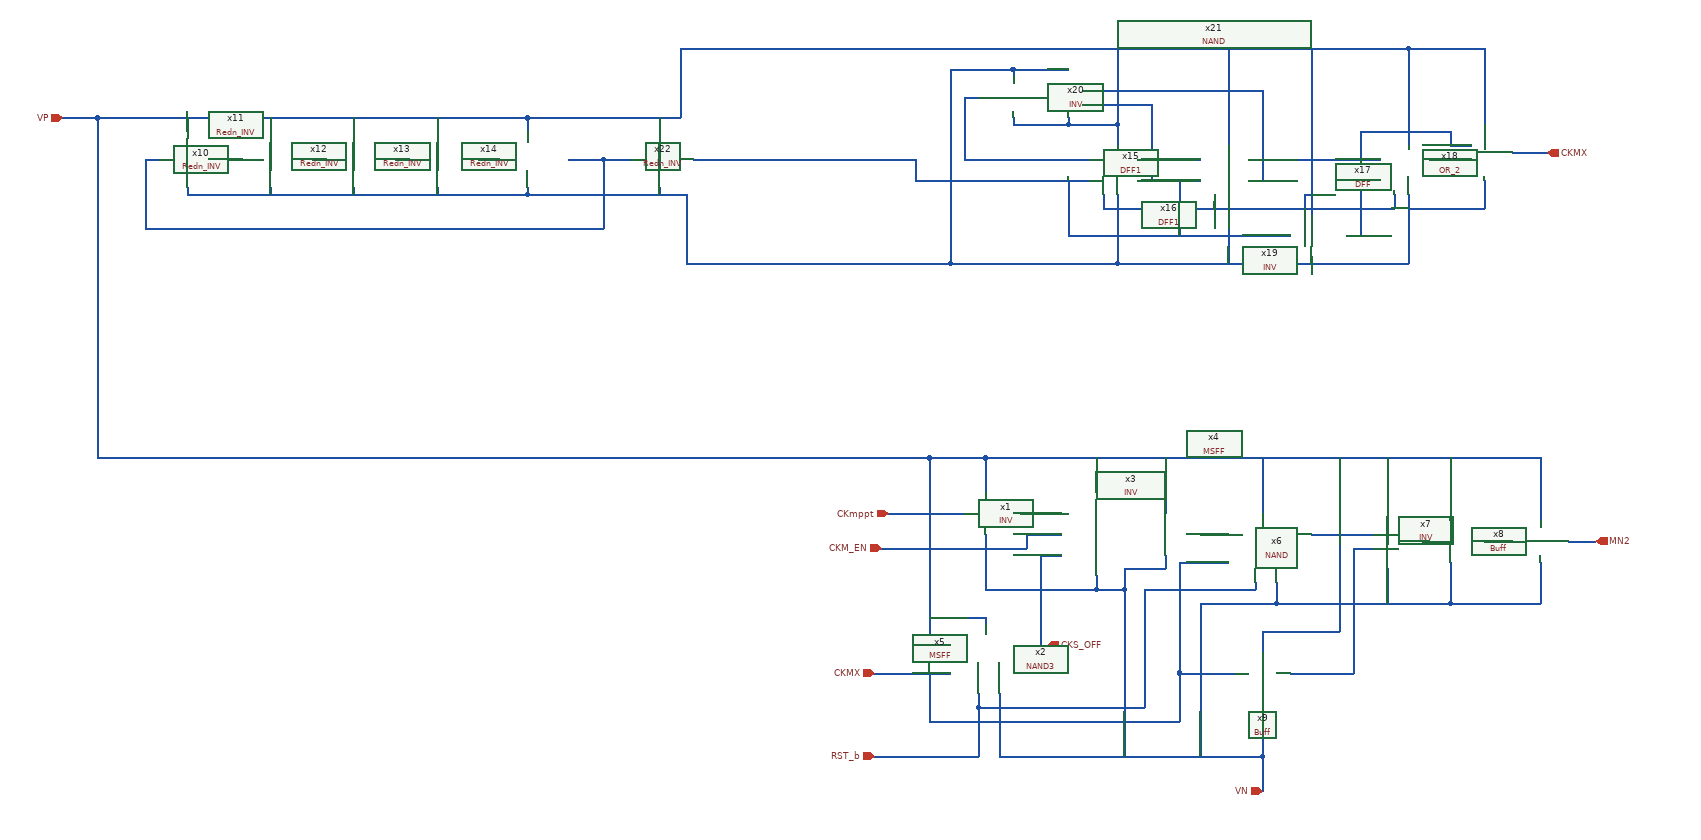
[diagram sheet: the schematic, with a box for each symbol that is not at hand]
v {xschem version=3.0.0 file_version=1.2 }
G {}
K {}
V {}
S {}
E {}
N 450 -550 510 -550 {
lab=#net1}
N 320 -550 370 -550 {
lab=CKmppt}
N 490 -520 510 -520 {
lab=CKmppt}
N 460 -520 490 -520 {
lab=CKmppt}
N 460 -520 460 -500 {
lab=CKmppt}
N 320 -500 460 -500 {
lab=CKmppt}
N 490 -490 510 -490 {
lab=CKS_OFF}
N 870 -520 960 -520 {
lab=#net2}
N 1120 -510 1160 -510 {
lab=#net3}
N 1240 -510 1280 -510 {
lab=MN2}
N 840 -320 930 -320 {
lab=#net4}
N 930 -500 930 -320 {
lab=#net4}
N 930 -500 960 -500 {
lab=#net4}
N 320 -360 350 -360 {
lab=CKmppt}
N 320 -420 320 -360 {
lab=CKmppt}
N 320 -400 380 -400 {
lab=CKmppt}
N 790 -450 790 -440 {
lab=RST_b}
N 290 -320 350 -320 {
lab=CKMX}
N 320 -320 320 -270 {
lab=CKMX}
N 320 -270 320 -250 {
lab=CKMX}
N 320 -250 680 -250 {
lab=CKMX}
N 680 -310 680 -250 {
lab=CKMX}
N 680 -320 680 -310 {
lab=CKMX}
N 680 -320 760 -320 {
lab=CKMX}
N 630 -400 630 -280 {
lab=RST_b}
N 390 -270 630 -270 {
lab=RST_b}
N 390 -290 390 -280 {
lab=RST_b}
N 630 -280 630 -270 {
lab=RST_b}
N 390 -280 390 -270 {
lab=RST_b}
N 390 -270 390 -200 {
lab=RST_b}
N 290 -200 390 -200 {
lab=RST_b}
N 240 -200 290 -200 {
lab=RST_b}
N 240 -320 290 -320 {
lab=CKMX}
N 250 -500 320 -500 {
lab=CKM_EN}
N 260 -550 320 -550 {
lab=CKmppt}
N 470 -360 490 -360 {
lab=CKS_OFF}
N 710 -520 750 -520 {
lab=#net5}
N 680 -450 680 -320 {
lab=CKMX}
N 700 -480 750 -480 {
lab=CKMX}
N 420 -290 420 -200 {
lab=#net6}
N 420 -200 800 -200 {
lab=#net6}
N 800 -290 800 -200 {
lab=#net6}
N 820 -450 820 -430 {
lab=#net6}
N 680 -480 680 -450 {
lab=CKMX}
N 680 -480 700 -480 {
lab=CKMX}
N 630 -440 630 -400 {
lab=RST_b}
N 630 -440 790 -440 {
lab=RST_b}
N 820 -430 820 -420 {
lab=#net6}
N 710 -420 820 -420 {
lab=#net6}
N 710 -420 710 -200 {
lab=#net6}
N 800 -200 800 -150 {
lab=#net6}
N 400 -520 400 -450 {
lab=#net6}
N 400 -450 400 -440 {
lab=#net6}
N 400 -440 560 -440 {
lab=#net6}
N 560 -460 560 -440 {
lab=#net6}
N 600 -440 600 -200 {
lab=#net6}
N 660 -490 660 -470 {
lab=#net6}
N 600 -470 660 -470 {
lab=#net6}
N 600 -470 600 -440 {
lab=#net6}
N 560 -440 600 -440 {
lab=#net6}
N 820 -420 990 -420 {
lab=#net6}
N 1200 -480 1200 -460 {
lab=#net6}
N 1070 -480 1070 -420 {
lab=#net6}
N 1200 -460 1200 -420 {
lab=#net6}
N 1070 -420 1200 -420 {
lab=#net6}
N 990 -420 1070 -420 {
lab=#net6}
N 400 -630 1190 -630 {
lab=CKmppt}
N 1190 -630 1200 -630 {
lab=CKmppt}
N 1200 -630 1200 -540 {
lab=CKmppt}
N 1070 -630 1070 -540 {
lab=CKmppt}
N 800 -630 800 -550 {
lab=CKmppt}
N 660 -630 660 -550 {
lab=CKmppt}
N 560 -630 560 -580 {
lab=CKmppt}
N 400 -630 400 -580 {
lab=CKmppt}
N 800 -380 800 -350 {
lab=CKmppt}
N 800 -380 910 -380 {
lab=CKmppt}
N 910 -630 910 -380 {
lab=CKmppt}
N 480 -490 490 -490 {
lab=CKS_OFF}
N 480 -490 480 -360 {
lab=CKS_OFF}
N 380 -400 400 -400 {
lab=CKmppt}
N 400 -400 400 -390 {
lab=CKmppt}
N 980 -630 980 -540 {
lab=CKmppt}
N 980 -470 980 -420 {
lab=#net6}
N 1030 -510 1040 -510 {
lab=#net7}
N -690 -1060 -670 -1060 {
lab=#net8}
N -570 -1060 -550 -1060 {
lab=#net9}
N -450 -1060 -430 -1060 {
lab=#net10}
N -330 -1060 -300 -1060 {
lab=#net11}
N -750 -1020 -750 -1010 {
lab=#net12}
N -750 -1010 -260 -1010 {
lab=#net12}
N -260 -1020 -260 -1010 {
lab=#net12}
N -390 -1020 -390 -1010 {
lab=#net12}
N -510 -1020 -510 -1010 {
lab=#net12}
N -630 -1020 -630 -1010 {
lab=#net12}
N -810 -1060 -790 -1060 {
lab=#net13}
N -810 -1060 -810 -960 {
lab=#net13}
N -200 -1060 -150 -1060 {
lab=#net13}
N -200 -1060 -150 -1060 {
lab=#net13}
N -810 -1120 -260 -1120 {
lab=CKmppt}
N -260 -1120 -260 -1100 {
lab=CKmppt}
N -390 -1120 -390 -1100 {
lab=CKmppt}
N -510 -1120 -510 -1100 {
lab=CKmppt}
N -630 -1120 -630 -1100 {
lab=CKmppt}
N -750 -1120 -750 -1100 {
lab=CKmppt}
N -150 -1060 -120 -1060 {
lab=#net13}
N -150 -1060 -150 -960 {
lab=#net13}
N -810 -960 -150 -960 {
lab=#net13}
N -260 -1120 -40 -1120 {
lab=CKmppt}
N -260 -1010 -30 -1010 {
lab=#net12}
N -120 -1060 -110 -1060 {
lab=#net13}
N 520 -1030 520 -980 {
lab=#net14}
N 680 -1030 710 -1030 {
lab=#net14}
N 750 -1110 750 -1080 {
lab=CKmppt}
N 590 -1110 590 -1080 {
lab=CKmppt}
N 520 -980 520 -960 {
lab=#net14}
N 520 -950 840 -950 {
lab=#net14}
N 920 -950 940 -950 {
lab=#net15}
N 940 -1030 940 -960 {
lab=#net15}
N 940 -1030 970 -1030 {
lab=#net15}
N 590 -1010 590 -910 {
lab=#net12}
N 590 -910 1010 -910 {
lab=#net12}
N 1010 -1010 1010 -910 {
lab=#net12}
N 750 -1010 750 -910 {
lab=#net12}
N 940 -960 940 -950 {
lab=#net15}
N 520 -960 520 -950 {
lab=#net14}
N 570 -1010 570 -990 {
lab=CKmppt}
N 870 -1110 870 -980 {
lab=CKmppt}
N 570 -990 990 -990 {
lab=CKmppt}
N 990 -1010 990 -990 {
lab=CKmppt}
N 730 -1010 730 -990 {
lab=CKmppt}
N 870 -920 870 -910 {
lab=#net12}
N 1010 -1110 1010 -1080 {
lab=CKmppt}
N 680 -1030 680 -950 {
lab=#net14}
N 350 -1220 520 -1220 {
lab=CKmppt}
N 520 -1220 1010 -1220 {
lab=CKmppt}
N 1010 -1220 1010 -1110 {
lab=CKmppt}
N 870 -1220 870 -1110 {
lab=CKmppt}
N 750 -1220 750 -1110 {
lab=CKmppt}
N 590 -1220 590 -1110 {
lab=CKmppt}
N 300 -1030 550 -1030 {
lab=#net14}
N 440 -910 590 -910 {
lab=#net12}
N 370 -1060 550 -1060 {
lab=#net16}
N 370 -1150 370 -1060 {
lab=#net16}
N 370 -1150 390 -1150 {
lab=#net16}
N 620 -1060 710 -1060 {
lab=#net17}
N 780 -1060 970 -1060 {
lab=#net18}
N 550 -1140 640 -1140 {
lab=#net19}
N 640 -1140 640 -1030 {
lab=#net19}
N 620 -1030 640 -1030 {
lab=#net19}
N 550 -1160 800 -1160 {
lab=#net20}
N 800 -1160 800 -1030 {
lab=#net20}
N 780 -1030 800 -1030 {
lab=#net20}
N 940 -1100 940 -1060 {
lab=#net18}
N 940 -1100 1070 -1100 {
lab=#net18}
N 1070 -1100 1070 -1080 {
lab=#net18}
N 1070 -1080 1100 -1080 {
lab=#net18}
N 1040 -1060 1100 -1060 {
lab=#net21}
N 1120 -1030 1120 -990 {
lab=#net12}
N 1010 -990 1120 -990 {
lab=#net12}
N 1010 -1220 1120 -1220 {
lab=CKmppt}
N 1120 -1220 1120 -1110 {
lab=CKmppt}
N 1160 -1070 1210 -1070 {
lab=CKMX}
N 440 -1190 520 -1190 {
lab=#net12}
N 440 -1190 440 -1180 {
lab=#net12}
N 350 -1190 440 -1190 {
lab=#net12}
N 350 -1190 350 -910 {
lab=#net12}
N 350 -910 440 -910 {
lab=#net12}
N 520 -1120 520 -1110 {
lab=CKmppt}
N 440 -1110 520 -1110 {
lab=CKmppt}
N 440 -1120 440 -1110 {
lab=CKmppt}
N 540 -1140 550 -1140 {
lab=#net19}
N 540 -1160 550 -1160 {
lab=#net20}
N 520 -1110 590 -1110 {
lab=CKmppt}
N 860 -1010 860 -990 {
lab=CKmppt}
N 860 -1010 870 -1010 {
lab=CKmppt}
N -10 -1060 300 -1060 {
lab=#net14}
N 300 -1060 300 -1030 {
lab=#net14}
N -40 -1210 -40 -1120 {
lab=CKmppt}
N -40 -1220 -40 -1210 {
lab=CKmppt}
N -40 -1220 350 -1220 {
lab=CKmppt}
N -30 -1010 -30 -910 {
lab=#net12}
N -30 -910 350 -910 {
lab=#net12}
N -20 -1060 -10 -1060 {
lab=#net14}
N -70 -1120 -70 -1100 {
lab=CKmppt}
N -70 -1020 -70 -1010 {
lab=#net12}
N 320 -630 320 -420 {
lab=CKmppt}
N 320 -630 400 -630 {
lab=CKmppt}
N -880 -630 320 -630 {
lab=CKmppt}
N -880 -1120 -880 -630 {
lab=CKmppt}
N -880 -1120 -810 -1120 {
lab=CKmppt}
N -930 -1120 -880 -1120 {
lab=VP}
C {devices/ipin.sym} 260 -550 0 0 {name=p1 lab=CKmppt}
C {devices/ipin.sym} 250 -500 0 0 {name=p2 lab=CKM_EN}
C {devices/ipin.sym} 240 -320 0 0 {name=p3 lab=CKMX}
C {devices/ipin.sym} 240 -200 0 0 {name=p4 lab=RST_b}
C {devices/opin.sym} 1280 -510 0 0 {name=p7 lab=MN2}
C {devices/opin.sym} 490 -360 0 0 {name=p8 lab=CKS_OFF}
C {Pico_project/FlipFlops/MSFF.sym} 720 -480 0 0 {name=x4}
C {Pico_project/NAND2/NAND.sym} 810 -460 0 0 {name=x6}
C {Pico_project/INV/INV.sym} 1020 -510 0 0 {name=x7}
C {Pico_project/FlipFlops/MSFF.sym} 320 -320 0 0 {name=x5}
C {Pico_project/INV/INV.sym} 610 -520 0 0 {name=x3}
C {Pico_project/INV/INV.sym} 350 -550 0 0 {name=x1}
C {Pico_project/Buffer/Buff.sym} 730 -320 0 0 {name=x9}
C {Pico_project/Buffer/Buff.sym} 1130 -510 0 0 {name=x8}
C {Pico_project/NAND3/NAND3.sym} 470 -480 0 0 {name=x2}
C {Pico_project/Rdn_INV/Redn_INV.sym} -830 -1020 0 0 {name=x10}
C {Pico_project/Rdn_INV/Redn_INV.sym} -710 -1020 0 0 {name=x11}
C {Pico_project/Rdn_INV/Redn_INV.sym} -590 -1020 0 0 {name=x12}
C {Pico_project/Rdn_INV/Redn_INV.sym} -470 -1020 0 0 {name=x13}
C {Pico_project/Rdn_INV/Redn_INV.sym} -340 -1020 0 0 {name=x14}
C {Pico_project/FlipFlops/DFF1.sym} 510 -1000 0 0 {name=x15}
C {Pico_project/FlipFlops/DFF1.sym} 670 -1000 0 0 {name=x16}
C {Pico_project/FlipFlops/DFF.sym} 930 -1000 0 0 {name=x17}
C {devices/opin.sym} 1210 -1070 0 0 {name=p10 lab=CKMX}
C {Pico_project/OR2/OR_2.sym} 1060 -1070 0 0 {name=x18}
C {Pico_project/INV/INV.sym} 820 -950 0 0 {name=x19}
C {Pico_project/INV/INV.sym} 490 -1150 2 0 {name=x20}
C {Pico_project/NAND2/NAND.sym} 690 -1200 2 0 {name=x21}
C {Pico_project/Rdn_INV/Redn_INV.sym} -150 -1020 0 0 {name=x22}
C {devices/iopin.sym} -930 -1120 2 0 {name=p9 lab=VP}
C {devices/iopin.sym} 800 -150 1 0 {name=p5 lab=VN}
